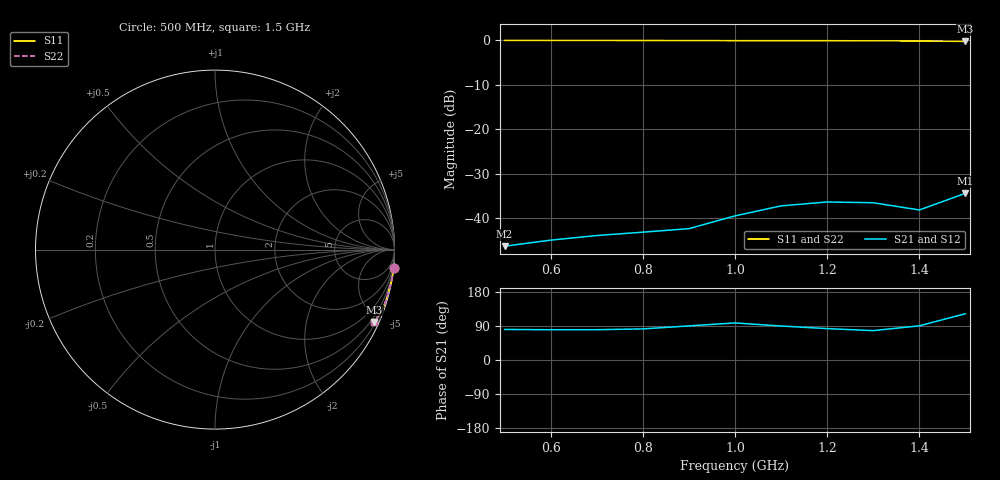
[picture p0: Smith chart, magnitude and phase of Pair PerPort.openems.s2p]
! Generated by circuitRF - EM: openEMS
! circuitRF-EM setup: Pair PerPort
! circuitRF-EM layout: Pair.c3d
! circuitRF-EM written: 2026-10-18 19:17:23Z
! circuitRF-EM geometry: ebda329beedeafbb
! circuitRF-EM mesh: 4c8efa042fff0f06
! circuitRF-EM ports: 8aadd8ff608c1838
! circuitRF-EM model: openEMS 0.37.0 (v0.37.0, CSXCAD v0.7.0)
! circuitRF-EM port 1: 'port/1' from 'aLo' to 'aHi', lumped, 50 Ohm
! circuitRF-EM port 2: 'port/2' from 'bLo' to 'bHi', lumped, 50 Ohm
! circuitRF-EM 3D grid: 33 x 34 x 41 = 46002 cells; smallest cell 1.25 mm on z, set by 'aLo' edge at z = -1.25 mm; 'bLo' edge at z = -1.25 mm; 'port/1' port extent at z = -1.25 mm; 'port/2' port extent at z = -1.25 mm; 'aHi' edge at z = 1.25 mm; 'bHi' edge at z = 1.25 mm; 'port/1' port extent at z =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
! circuitRF-EM 3D openEMS run port 1: dt 3.03235E-12 s (estimate 3.00252E-12 s), 6000 steps, port signals 101.6 dB and energy unreported against 200 dB, stopped at the step limit, NOT converged
! circuitRF-EM 3D openEMS run port 2: dt 3.03235E-12 s (estimate 3.00252E-12 s), 6000 steps, port signals 101.6 dB and energy unreported against 200 dB, stopped at the step limit, NOT converged
! circuitRF-EM 3D dielectric loss fitted at: 1 GHz
! circuitRF-EM 3D perfect conductors: aLo, aHi, bLo, bHi
! circuitRF-EM 3D operating temperature: 20 C
! circuitRF-EM 3D port fields: 'Pair PerPort.openems.fields' stamp 20261018T191722Z-11a8af39
! circuitRF-EM: re-running the EM setup rewrites this file. If circuitRF reports it as stale, the layout's cross-section changed after this file was written.
# GHz S RI R 50
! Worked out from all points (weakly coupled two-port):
!   11 points, 500 MHz to 1.5 GHz, reference 50 ohm
!   highest |S21| = -34.44 dB at 1.5 GHz (marker M1); lowest = -46.4 dB at 500 MHz (marker M2)
!   lowest |S11| = -0.2 dB at 1.5 GHz (marker M3), VSWR 80.83, Z = 13.8 - j230 ohm
!   |S11| at or under -10 dB: nowhere
!   |S22| runs from -0.2 to 0.0 dB; largest |S21 - S12| = 9.8e-08
0.5  0.995 -0.1021  0.000784 0.00475  0.000784 0.00475  0.995 -0.1021
0.6  0.9925 -0.1244  0.000991 0.00554  0.000991 0.00554  0.9925 -0.1244
0.7  0.989 -0.1479  0.0011 0.00625  0.0011 0.00625  0.989 -0.1479
0.8  0.9843 -0.1728  0.000957 0.00685  0.000957 0.00685  0.9843 -0.1728
0.9  0.9774 -0.1989  1.64e-06 0.00758  1.64e-06 0.00758  0.9774 -0.1989
1  0.9693 -0.2245  -0.00144 0.0105  -0.00144 0.0105  0.9693 -0.2245
1.1  0.9623 -0.253  6.78e-05 0.0137  6.78e-05 0.0137  0.9623 -0.253
1.2  0.952 -0.2863  0.0019 0.015  0.0019 0.015  0.952 -0.2863
1.3  0.9364 -0.3224  0.00322 0.0145  0.00322 0.0145  0.9364 -0.3224
1.4  0.9169 -0.3607  -4.55e-05 0.0123  -4.55e-05 0.0123  0.9169 -0.3607
1.5  0.8881 -0.4036  -0.0101 0.0161  -0.0101 0.0161  0.8881 -0.4036
